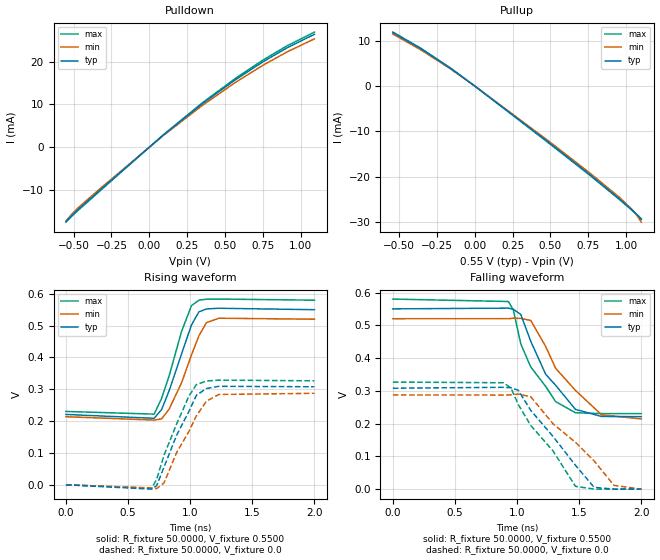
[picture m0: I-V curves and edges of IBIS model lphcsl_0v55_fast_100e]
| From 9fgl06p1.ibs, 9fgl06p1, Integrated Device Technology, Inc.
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[Model]   lphcsl_0v55_fast_100e
Model_type Output
Polarity   Non-Inverting
Enable   Active-High
Vmeas =  0.4000V
Cref =   2.0000pF
Rref =   0.0
Vref =   0.4000V
C_comp   1.1000pF   1.0000pF   1.2000pF
[Temperature Range]   25.0000   85.0000   -40.0
[Voltage Range]   0.5500V   0.5200V   0.5800V
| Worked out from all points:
|   slope of the pulldown table from 0 to 0.083 V, typ, clamps not added: 32.7 ohm
|   slope of the pullup table from 0 to 0.083 V, typ, clamps not added: 39.3 ohm
|   rising waveform, R_fixture 50.0000, V_fixture 0.5500: 20-80 % time 174ps typ, 180ps min, 165ps max; typ from 0.221 V to 0.55 V
|   rising waveform, R_fixture 50.0000, V_fixture 0.0: 20-80 % time 210ps typ, 226ps min, 201ps max; typ from 0 V to 0.308 V
|   falling waveform, R_fixture 50.0000, V_fixture 0.5500: 20-80 % time 295ps typ, 339ps min, 258ps max; typ from 0.55 V to 0.221 V
|   falling waveform, R_fixture 50.0000, V_fixture 0.0: 20-80 % time 385ps typ, 441ps min, 351ps max; typ from 0.308 V to 0 V
[Pulldown]
|Voltage   I(typ)   I(min)   I(max)
-550mV    -17.42mA   -17.31mA   -17.56mA
-510mV    -15.92mA   -15.61mA   -16.12mA
-470mV    -14.59mA   -14.21mA   -14.8mA
-310mV    -9.584mA   -9.264mA   -9.753mA
90mV      2.747mA    2.637mA    2.806mA
350mV     10.16mA    9.756mA    10.37mA
570mV     15.8mA     15.17mA    16.12mA
750mV     19.95mA    19.15mA    20.36mA
910mV     23.24mA    22.29mA    23.72mA
1.09V     26.39mA    25.32mA    26.91mA
[Pullup]
|Voltage   I(typ)   I(min)   I(max)
-540mV    11.78mA    11.45mA    11.88mA
-360mV    8.313mA    8.057mA    8.417mA
-160mV    3.912mA    3.778mA    3.974mA
0V        -107.6pA   -683pA     -85.53pA
480mV     -12.23mA   -11.94mA   -12.36mA
760mV     -19.55mA   -19.19mA   -19.69mA
960mV     -25.05mA   -24.7mA    -25.17mA
1.04V     -27.39mA   -27.28mA   -27.47mA
1.08V     -28.69mA   -28.98mA   -28.66mA
1.1V      -29.42mA   -30.05mA   -29.29mA
[Ramp]
| variable   typ   min   max
dV/dt_r  0.1848/0.2165n   0.1724/0.2461n   0.1960/0.2011n
dV/dt_f  0.1973/0.2848n   0.1835/0.3291n   0.2098/0.2758n
R_load = 50.0000
[Rising Waveform]
R_fixture= 50.0000
V_fixture= 0.5500
V_fixture_min= 0.5200
V_fixture_max= 0.5800
|time   V(typ)   V(min)   V(max)
0s        221mV      213.9mV    230.4mV
710ps     208.9mV    203.3mV    222mV
770ps     236.5mV    207.1mV    271.8mV
830ps     295.1mV    237.4mV    341.4mV
930ps     410.6mV    320mV      481.3mV
1.01ns    502mV      407.6mV    562.8mV
1.07ns    543.3mV    467.9mV    580.1mV
1.13ns    552.4mV    509.1mV    583mV
1.23ns    554.6mV    523.3mV    583.5mV
2ns       550.1mV    520.2mV    580mV
[Rising Waveform]
R_fixture= 50.0000
V_fixture= 0.0
V_fixture_min= 0.0
V_fixture_max= 0.0
|time   V(typ)   V(min)   V(max)
0s        0V         0V         0V
690ps     -13.76mV   -9.908mV   -11mV
730ps     -2.555mV   -12mV      17.28mV
790ps     56.31mV    6.206mV    93.42mV
890ps     155mV      100.6mV    190.4mV
990ps     231mV      167.8mV    278.9mV
1.05ns    281.3mV    216.8mV    314.6mV
1.13ns    302.4mV    262.5mV    326.1mV
1.23ns    309.3mV    283.7mV    328.7mV
2ns       308mV      287.4mV    326.7mV
[Falling Waveform]
R_fixture= 50.0000
V_fixture= 0.5500
V_fixture_min= 0.5200
V_fixture_max= 0.5800
|time   V(typ)   V(min)   V(max)
0s        550mV      520mV      580mV
930ps     552.4mV    520.1mV    572.5mV
970ps     548.8mV    521.6mV    546.6mV
1.03ns    533mV      521mV      442.9mV
1.11ns    451.2mV    514.7mV    373mV
1.23ns    350.6mV    435.4mV    313.4mV
1.31ns    317mV      368.9mV    267.2mV
1.47ns    243.2mV    301.1mV    233mV
1.68ns    221.7mV    226.8mV    230.4mV
2ns       221.1mV    214.1mV    230.4mV
[Falling Waveform]
R_fixture= 50.0000
V_fixture= 0.0
V_fixture_min= 0.0
V_fixture_max= 0.0
|time   V(typ)   V(min)   V(max)
0s        307.9mV    287.3mV    326.7mV
890ps     310.7mV    287.1mV    324.6mV
950ps     309.3mV    287.8mV    308.9mV
1.01ns    301.5mV    290mV      257.9mV
1.11ns    240.4mV    281.8mV    194.3mV
1.29ns    160.4mV    199.1mV    116.1mV
1.47ns    72.59mV    142.7mV    8.438mV
1.62ns    5.493mV    86.02mV    77.42uV
1.78ns    -65.96uV   11.35mV    -85.75uV
2ns       -77.45uV   -198.5uV   -34.61uV
